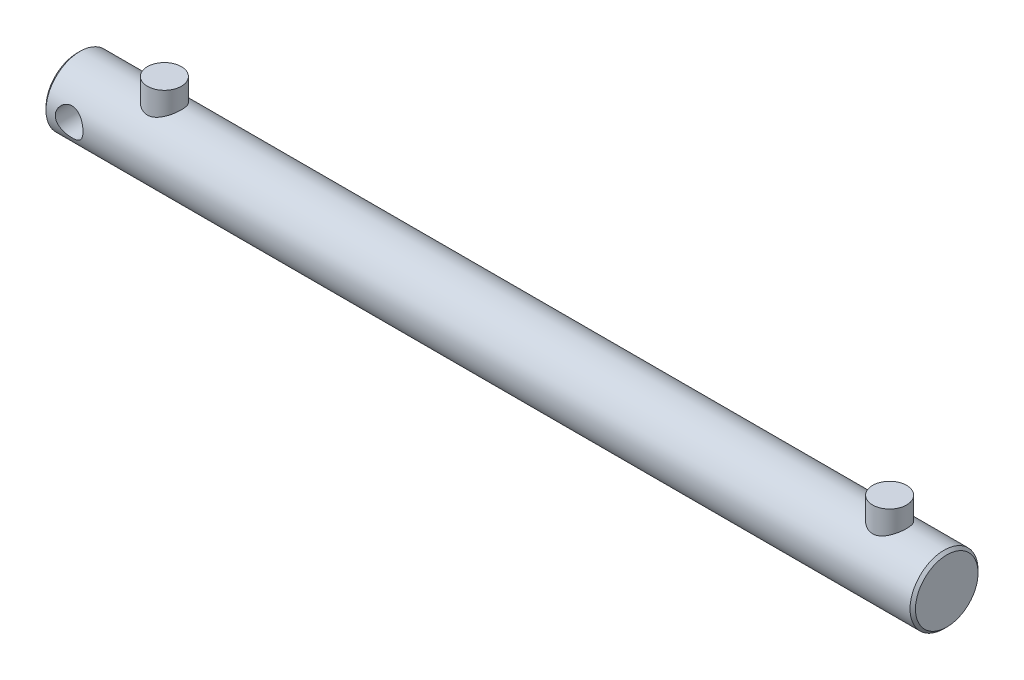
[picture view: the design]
ISO-10303-21;
HEADER;
FILE_DESCRIPTION(('STEP AP214'),'2;1');
FILE_NAME('part.step','',(''),(''),'','','');
FILE_SCHEMA(('AUTOMOTIVE_DESIGN { 1 0 10303 214 1 1 1 1 }'));
ENDSEC;
DATA;
#1=APPLICATION_CONTEXT('core data for automotive mechanical design processes');
#2=APPLICATION_PROTOCOL_DEFINITION('international standard','automotive_design',2000,#1);
#3=PRODUCT_CONTEXT('',#1,'mechanical');
#4=PRODUCT('Part','Part','',(#3));
#5=PRODUCT_RELATED_PRODUCT_CATEGORY('part','',(#4));
#6=PRODUCT_DEFINITION_FORMATION('','',#4);
#7=PRODUCT_DEFINITION_CONTEXT('part definition',#1,'design');
#8=PRODUCT_DEFINITION('design','',#6,#7);
#9=PRODUCT_DEFINITION_SHAPE('','',#8);
#10=(LENGTH_UNIT() NAMED_UNIT(*) SI_UNIT(.MILLI.,.METRE.));
#11=(NAMED_UNIT(*) PLANE_ANGLE_UNIT() SI_UNIT($,.RADIAN.));
#12=(NAMED_UNIT(*) SI_UNIT($,.STERADIAN.) SOLID_ANGLE_UNIT());
#13=UNCERTAINTY_MEASURE_WITH_UNIT(LENGTH_MEASURE(1.E-05),#10,'distance_accuracy_value','');
#14=(GEOMETRIC_REPRESENTATION_CONTEXT(3) GLOBAL_UNCERTAINTY_ASSIGNED_CONTEXT((#13)) GLOBAL_UNIT_ASSIGNED_CONTEXT((#10,
#11,#12)) REPRESENTATION_CONTEXT('',''));
#15=CARTESIAN_POINT('',(0.,0.,0.));
#16=DIRECTION('',(0.,0.,1.));
#17=DIRECTION('',(1.,0.,0.));
#18=AXIS2_PLACEMENT_3D('',#15,#16,#17);
#19=CARTESIAN_POINT('',(-319.5,0.,0.));
#20=DIRECTION('',(-1.,0.,0.));
#21=DIRECTION('',(0.,0.,1.));
#22=AXIS2_PLACEMENT_3D('',#19,#20,#21);
#23=CYLINDRICAL_SURFACE('',#22,25.);
#24=CARTESIAN_POINT('',(-255.5,21.6506350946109,-12.5));
#25=CARTESIAN_POINT('',(-255.825828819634,21.6506369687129,-12.4999985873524));
#26=CARTESIAN_POINT('',(-256.151686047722,21.6580155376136,-12.4872432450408));
#27=CARTESIAN_POINT('',(-256.800889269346,21.6872558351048,-12.4363891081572));
#28=CARTESIAN_POINT('',(-257.12423402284,21.7091243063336,-12.3982785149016));
#29=CARTESIAN_POINT('',(-257.766364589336,21.7665787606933,-12.297130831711));
#30=CARTESIAN_POINT('',(-258.085140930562,21.802189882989,-12.2340480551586));
#31=CARTESIAN_POINT('',(-258.715226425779,21.8858435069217,-12.0837589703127));
#32=CARTESIAN_POINT('',(-259.026536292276,21.9338848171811,-11.9965549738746));
#33=CARTESIAN_POINT('',(-259.638091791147,22.0405000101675,-11.7995262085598));
#34=CARTESIAN_POINT('',(-259.938389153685,22.0990140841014,-11.6898294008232));
#35=CARTESIAN_POINT('',(-260.528172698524,22.2249725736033,-11.4485414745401));
#36=CARTESIAN_POINT('',(-260.817654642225,22.2924204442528,-11.3169418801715));
#37=CARTESIAN_POINT('',(-261.667464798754,22.5052717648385,-10.8909843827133));
#38=CARTESIAN_POINT('',(-262.2097361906,22.6612898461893,-10.5652792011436));
#39=CARTESIAN_POINT('',(-263.278979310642,22.9996468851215,-9.80822889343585));
#40=CARTESIAN_POINT('',(-263.801000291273,23.1830954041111,-9.37038644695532));
#41=CARTESIAN_POINT('',(-264.525932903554,23.4556474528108,-8.65437620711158));
#42=CARTESIAN_POINT('',(-264.75804289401,23.5461267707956,-8.40562738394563));
#43=CARTESIAN_POINT('',(-265.201667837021,23.7240607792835,-7.88944454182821));
#44=CARTESIAN_POINT('',(-265.413190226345,23.8115165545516,-7.62201733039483));
#45=CARTESIAN_POINT('',(-265.827960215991,23.9870610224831,-7.0509634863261));
#46=CARTESIAN_POINT('',(-266.029675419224,24.0747909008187,-6.74611185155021));
#47=CARTESIAN_POINT('',(-266.406506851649,24.2419754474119,-6.11818329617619));
#48=CARTESIAN_POINT('',(-266.581621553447,24.3214296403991,-5.79510533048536));
#49=CARTESIAN_POINT('',(-266.90343651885,24.4697359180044,-5.13293948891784));
#50=CARTESIAN_POINT('',(-267.050150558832,24.5385931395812,-4.79385947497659));
#51=CARTESIAN_POINT('',(-267.313578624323,24.663681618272,-4.10199116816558));
#52=CARTESIAN_POINT('',(-267.430295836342,24.7199142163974,-3.74920433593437));
#53=CARTESIAN_POINT('',(-267.625035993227,24.8145076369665,-3.05827019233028));
#54=CARTESIAN_POINT('',(-267.70522088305,24.8538552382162,-2.72086672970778));
#55=CARTESIAN_POINT('',(-267.837413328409,24.9190379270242,-2.03929145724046));
#56=CARTESIAN_POINT('',(-267.889422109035,24.9448736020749,-1.69511994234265));
#57=CARTESIAN_POINT('',(-267.964549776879,24.9822725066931,-1.00304268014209));
#58=CARTESIAN_POINT('',(-267.987683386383,24.9938430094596,-0.655138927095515));
#59=CARTESIAN_POINT('',(-268.004785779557,25.0023919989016,0.04155519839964));
#60=CARTESIAN_POINT('',(-267.998756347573,24.9993713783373,0.390345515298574));
#61=CARTESIAN_POINT('',(-267.959420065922,24.9797298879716,1.05545670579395));
#62=CARTESIAN_POINT('',(-267.928534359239,24.9643162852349,1.3719600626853));
#63=CARTESIAN_POINT('',(-267.842896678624,24.9217919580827,2.00090286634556));
#64=CARTESIAN_POINT('',(-267.788146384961,24.8946820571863,2.31334259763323));
#65=CARTESIAN_POINT('',(-267.655375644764,24.8294144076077,2.93205832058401));
#66=CARTESIAN_POINT('',(-267.577354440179,24.7912562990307,3.2383341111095));
#67=CARTESIAN_POINT('',(-267.398835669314,24.7047808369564,3.8427892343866));
#68=CARTESIAN_POINT('',(-267.298337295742,24.6564631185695,4.14096827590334));
#69=CARTESIAN_POINT('',(-267.074267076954,24.5500266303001,4.73153890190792));
#70=CARTESIAN_POINT('',(-266.950396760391,24.4917821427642,5.02379438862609));
#71=CARTESIAN_POINT('',(-266.681577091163,24.367262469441,5.59664626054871));
#72=CARTESIAN_POINT('',(-266.536627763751,24.3009872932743,5.87724265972));
#73=CARTESIAN_POINT('',(-266.226722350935,24.1618170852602,6.42546402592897));
#74=CARTESIAN_POINT('',(-266.061764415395,24.0889214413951,6.69308779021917));
#75=CARTESIAN_POINT('',(-265.712866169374,23.9380009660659,7.21427443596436));
#76=CARTESIAN_POINT('',(-265.528918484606,23.8599741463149,7.46783179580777));
#77=CARTESIAN_POINT('',(-265.124909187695,23.6928666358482,7.98299107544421));
#78=CARTESIAN_POINT('',(-264.903077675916,23.6034377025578,8.24309375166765));
#79=CARTESIAN_POINT('',(-264.439270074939,23.4225308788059,8.74390948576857));
#80=CARTESIAN_POINT('',(-264.197292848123,23.331052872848,8.9846214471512));
#81=CARTESIAN_POINT('',(-263.694268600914,23.1482419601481,9.44565668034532));
#82=CARTESIAN_POINT('',(-263.433209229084,23.0569091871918,9.66596653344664));
#83=CARTESIAN_POINT('',(-262.893337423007,22.8767716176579,10.0849060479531));
#84=CARTESIAN_POINT('',(-262.614521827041,22.7879672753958,10.2835318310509));
#85=CARTESIAN_POINT('',(-262.022086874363,22.6097947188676,10.6698301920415));
#86=CARTESIAN_POINT('',(-261.707381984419,22.520752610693,10.8559934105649));
#87=CARTESIAN_POINT('',(-261.061183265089,22.3512779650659,11.2007713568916));
#88=CARTESIAN_POINT('',(-260.729697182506,22.2708415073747,11.3593986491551));
#89=CARTESIAN_POINT('',(-260.051996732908,22.1215174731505,11.6475234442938));
#90=CARTESIAN_POINT('',(-259.705791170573,22.0526231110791,11.7770380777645));
#91=CARTESIAN_POINT('',(-259.000945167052,21.9291206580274,12.0054389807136));
#92=CARTESIAN_POINT('',(-258.642306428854,21.874510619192,12.1043294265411));
#93=CARTESIAN_POINT('',(-257.944369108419,21.7856557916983,12.26347567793));
#94=CARTESIAN_POINT('',(-257.605788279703,21.7501406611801,12.3261709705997));
#95=CARTESIAN_POINT('',(-256.923342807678,21.6947067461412,12.4234802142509));
#96=CARTESIAN_POINT('',(-256.579478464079,21.6747870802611,12.4580957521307));
#97=CARTESIAN_POINT('',(-255.889711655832,21.6514003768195,12.4986965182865));
#98=CARTESIAN_POINT('',(-255.543810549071,21.6479233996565,12.5046990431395));
#99=CARTESIAN_POINT('',(-254.852946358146,21.657548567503,12.4880218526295));
#100=CARTESIAN_POINT('',(-254.50798321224,21.6706495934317,12.4653440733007));
#101=CARTESIAN_POINT('',(-253.859787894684,21.7105357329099,12.3957257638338));
#102=CARTESIAN_POINT('',(-253.556131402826,21.7356609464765,12.3517217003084));
#103=CARTESIAN_POINT('',(-252.953946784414,21.7977675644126,12.2417856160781));
#104=CARTESIAN_POINT('',(-252.655420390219,21.8347528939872,12.1758463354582));
#105=CARTESIAN_POINT('',(-252.065469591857,21.919415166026,12.0227647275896));
#106=CARTESIAN_POINT('',(-251.774044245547,21.9670906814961,11.9356252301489));
#107=CARTESIAN_POINT('',(-251.199706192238,22.0717635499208,11.7409310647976));
#108=CARTESIAN_POINT('',(-250.916796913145,22.1287645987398,11.6333683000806));
#109=CARTESIAN_POINT('',(-250.348184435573,22.2533312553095,11.3933466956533));
#110=CARTESIAN_POINT('',(-250.062947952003,22.3212614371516,11.2599724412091));
#111=CARTESIAN_POINT('',(-249.504535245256,22.4638079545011,10.9728312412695));
#112=CARTESIAN_POINT('',(-249.231364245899,22.5384271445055,10.8190555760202));
#113=CARTESIAN_POINT('',(-248.698252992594,22.692479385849,10.4920939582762));
#114=CARTESIAN_POINT('',(-248.438315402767,22.7719133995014,10.3189041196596));
#115=CARTESIAN_POINT('',(-247.932706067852,22.933742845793,9.95405785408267));
#116=CARTESIAN_POINT('',(-247.687035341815,23.0161384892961,9.76240011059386));
#117=CARTESIAN_POINT('',(-247.180799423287,23.192583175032,9.33615452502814));
#118=CARTESIAN_POINT('',(-246.922274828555,23.2867891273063,9.09920221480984));
#119=CARTESIAN_POINT('',(-246.425930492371,23.4741545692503,8.6043043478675));
#120=CARTESIAN_POINT('',(-246.188104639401,23.5673143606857,8.34636503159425));
#121=CARTESIAN_POINT('',(-245.734261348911,23.7502946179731,7.81048740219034));
#122=CARTESIAN_POINT('',(-245.518260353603,23.8401125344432,7.53253427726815));
#123=CARTESIAN_POINT('',(-245.109811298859,24.0139935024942,6.95830888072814));
#124=CARTESIAN_POINT('',(-244.917353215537,24.0980589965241,6.66204448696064));
#125=CARTESIAN_POINT('',(-244.552580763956,24.2604327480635,6.04450287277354));
#126=CARTESIAN_POINT('',(-244.380942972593,24.3385268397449,5.72276854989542));
#127=CARTESIAN_POINT('',(-244.065661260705,24.4841693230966,5.06353477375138));
#128=CARTESIAN_POINT('',(-243.922018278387,24.5517173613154,4.72603479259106));
#129=CARTESIAN_POINT('',(-243.664459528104,24.6742211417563,4.03792427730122));
#130=CARTESIAN_POINT('',(-243.55052252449,24.7291858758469,3.6873233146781));
#131=CARTESIAN_POINT('',(-243.353726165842,24.8248778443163,2.97561663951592));
#132=CARTESIAN_POINT('',(-243.270863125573,24.8656067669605,2.61451217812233));
#133=CARTESIAN_POINT('',(-243.143513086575,24.9284979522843,1.9185062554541));
#134=CARTESIAN_POINT('',(-243.096201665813,24.9520213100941,1.58424214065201));
#135=CARTESIAN_POINT('',(-243.028766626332,24.985611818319,0.912314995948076));
#136=CARTESIAN_POINT('',(-243.00864128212,24.9956798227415,0.574652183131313));
#137=CARTESIAN_POINT('',(-242.995841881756,25.0020787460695,-0.101219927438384));
#138=CARTESIAN_POINT('',(-243.003159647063,24.9984137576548,-0.439429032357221));
#139=CARTESIAN_POINT('',(-243.045132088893,24.9774578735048,-1.11371445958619));
#140=CARTESIAN_POINT('',(-243.079786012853,24.96016735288,-1.4497908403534));
#141=CARTESIAN_POINT('',(-243.172800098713,24.9140191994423,-2.09506424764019));
#142=CARTESIAN_POINT('',(-243.229444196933,24.8860005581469,-2.40457105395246));
#143=CARTESIAN_POINT('',(-243.365571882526,24.8191625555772,-3.01730683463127));
#144=CARTESIAN_POINT('',(-243.445054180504,24.7803438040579,-3.32053616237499));
#145=CARTESIAN_POINT('',(-243.626075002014,24.6927888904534,-3.91887965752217));
#146=CARTESIAN_POINT('',(-243.727615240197,24.644051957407,-4.21399319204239));
#147=CARTESIAN_POINT('',(-243.951830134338,24.5377360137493,-4.79443241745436));
#148=CARTESIAN_POINT('',(-244.074505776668,24.4801565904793,-5.07975765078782));
#149=CARTESIAN_POINT('',(-244.345646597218,24.3547642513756,-5.65106966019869));
#150=CARTESIAN_POINT('',(-244.494986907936,24.2866201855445,-5.93656816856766));
#151=CARTESIAN_POINT('',(-244.814454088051,24.1435393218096,-6.49402514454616));
#152=CARTESIAN_POINT('',(-244.984588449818,24.0686000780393,-6.76597868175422));
#153=CARTESIAN_POINT('',(-245.344503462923,23.9135470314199,-7.29508667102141));
#154=CARTESIAN_POINT('',(-245.534288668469,23.8334320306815,-7.55223767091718));
#155=CARTESIAN_POINT('',(-245.93236125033,23.6697443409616,-8.05059010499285));
#156=CARTESIAN_POINT('',(-246.140648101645,23.5861717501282,-8.29179199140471));
#157=CARTESIAN_POINT('',(-246.596332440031,23.4089075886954,-8.78049915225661));
#158=CARTESIAN_POINT('',(-246.845558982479,23.3150375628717,-9.02623729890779));
#159=CARTESIAN_POINT('',(-247.363805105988,23.1276739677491,-9.49603431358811));
#160=CARTESIAN_POINT('',(-247.632825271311,23.0341804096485,-9.72009254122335));
#161=CARTESIAN_POINT('',(-248.189584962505,22.8500132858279,-10.1454748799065));
#162=CARTESIAN_POINT('',(-248.477340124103,22.7593421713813,-10.3467796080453));
#163=CARTESIAN_POINT('',(-249.07002865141,22.5834994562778,-10.7251617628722));
#164=CARTESIAN_POINT('',(-249.374964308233,22.498328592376,-10.9022359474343));
#165=CARTESIAN_POINT('',(-250.010467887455,22.3335584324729,-11.2360101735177));
#166=CARTESIAN_POINT('',(-250.341543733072,22.2542245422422,-11.3918772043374));
#167=CARTESIAN_POINT('',(-251.018159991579,22.1071923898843,-11.6746502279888));
#168=CARTESIAN_POINT('',(-251.363692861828,22.0394881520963,-11.8015711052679));
#169=CARTESIAN_POINT('',(-252.066013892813,21.9185525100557,-12.0246888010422));
#170=CARTESIAN_POINT('',(-252.422770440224,21.8652839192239,-12.1209646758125));
#171=CARTESIAN_POINT('',(-253.145231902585,21.7753691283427,-12.2817688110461));
#172=CARTESIAN_POINT('',(-253.510930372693,21.7387113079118,-12.346319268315));
#173=CARTESIAN_POINT('',(-254.147494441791,21.6911886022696,-12.4295575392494));
#174=CARTESIAN_POINT('',(-254.417060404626,21.6760179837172,-12.4559482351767));
#175=CARTESIAN_POINT('',(-254.957744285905,21.6557401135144,-12.4911706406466));
#176=CARTESIAN_POINT('',(-255.228862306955,21.6506335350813,-12.5000011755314));
#177=CARTESIAN_POINT('',(-255.5,21.6506350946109,-12.5));
#178=B_SPLINE_CURVE_WITH_KNOTS('',3,(#24,#25,#26,#27,#28,#29,#30,#31,#32,#33,#34,#35,#36,#37,
#38,#39,#40,#41,#42,#43,#44,#45,#46,#47,#48,#49,#50,#51,#52,#53,#54,#55,#56,#57,#58,#59,#60,#61,
#62,#63,#64,#65,#66,#67,#68,#69,#70,#71,#72,#73,#74,#75,#76,#77,#78,#79,#80,#81,#82,#83,#84,#85,
#86,#87,#88,#89,#90,#91,#92,#93,#94,#95,#96,#97,#98,#99,#100,#101,#102,#103,#104,#105,#106,#107,
#108,#109,#110,#111,#112,#113,#114,#115,#116,#117,#118,#119,#120,#121,#122,#123,#124,#125,#126,
#127,#128,#129,#130,#131,#132,#133,#134,#135,#136,#137,#138,#139,#140,#141,#142,#143,#144,#145,
#146,#147,#148,#149,#150,#151,#152,#153,#154,#155,#156,#157,#158,#159,#160,#161,#162,#163,#164,
#165,#166,#167,#168,#169,#170,#171,#172,#173,#174,#175,#176,#177),.UNSPECIFIED.,.T.,.F.,(4,2,2,
2,2,2,2,2,2,2,2,2,2,2,2,2,2,2,2,2,2,2,2,2,2,2,2,2,2,2,2,2,2,2,2,2,2,2,2,2,2,2,2,2,2,2,2,2,2,2,2,
2,2,2,2,2,2,2,2,2,2,2,2,2,2,2,2,2,2,2,2,2,2,2,2,2,4),(0.,0.977205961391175,1.95486696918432,
2.93432493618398,3.91368906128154,4.88762893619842,5.86194658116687,7.80874820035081,
9.91611803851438,10.9713526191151,12.0262045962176,13.1525478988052,14.2789558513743,
15.4048160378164,16.5305565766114,17.5762155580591,18.6218290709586,19.6669092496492,
20.7119254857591,21.6659378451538,22.6198830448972,23.5738593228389,24.5278698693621,
25.4950080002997,26.4621449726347,27.4293714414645,28.39697493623,29.4558985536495,
30.514882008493,31.5745570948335,32.6344214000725,33.7619649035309,34.8889925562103,
36.015355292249,37.1415643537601,38.17858119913,39.2155394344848,40.251870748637,
41.2881321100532,42.2106469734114,43.1334674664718,44.0561648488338,44.9792288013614,
45.9446183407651,46.9104218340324,47.8764189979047,48.8424850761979,49.9306247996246,
51.0184421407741,52.1070729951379,53.1952387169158,54.3125134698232,55.429825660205,
56.5463369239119,57.6627157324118,58.6766202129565,59.6904603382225,60.7039983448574,
61.7175084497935,62.6641089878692,63.6106560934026,64.5572768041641,65.5039417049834,
66.4908805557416,67.478176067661,68.4657009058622,69.4531977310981,70.5391008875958,
71.6250361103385,72.71188954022,73.7988882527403,74.9206611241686,76.0418558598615,
77.1601343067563,78.2776292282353,79.0907545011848,79.9039341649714),.UNSPECIFIED.);
#179=CARTESIAN_POINT('',(-255.5,21.6506350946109,-12.5));
#180=VERTEX_POINT('',#179);
#181=EDGE_CURVE('E38',#180,#180,#178,.T.);
#182=ORIENTED_EDGE('',*,*,#181,.F.);
#183=EDGE_LOOP('',(#182));
#184=FACE_BOUND('',#183,.T.);
#185=CARTESIAN_POINT('',(-290.3,0.,-24.9999999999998));
#186=CARTESIAN_POINT('',(-290.300001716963,0.27378943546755,-24.9999986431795));
#187=CARTESIAN_POINT('',(-290.311038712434,0.547678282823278,-24.9954899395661));
#188=CARTESIAN_POINT('',(-290.355085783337,1.09351246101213,-24.9775677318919));
#189=CARTESIAN_POINT('',(-290.388110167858,1.36545640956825,-24.9641484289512));
#190=CARTESIAN_POINT('',(-290.475895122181,1.90589153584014,-24.9287196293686));
#191=CARTESIAN_POINT('',(-290.530705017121,2.17437344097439,-24.9066906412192));
#192=CARTESIAN_POINT('',(-290.661508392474,2.70533868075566,-24.8546237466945));
#193=CARTESIAN_POINT('',(-290.737503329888,2.96782160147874,-24.8245852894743));
#194=CARTESIAN_POINT('',(-290.909657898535,3.48412634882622,-24.7573909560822));
#195=CARTESIAN_POINT('',(-291.005747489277,3.73797478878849,-24.7202598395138));
#196=CARTESIAN_POINT('',(-291.217413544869,4.23637900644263,-24.6397409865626));
#197=CARTESIAN_POINT('',(-291.332990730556,4.48093443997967,-24.5963530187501));
#198=CARTESIAN_POINT('',(-291.582658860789,4.95920699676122,-24.5043977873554));
#199=CARTESIAN_POINT('',(-291.71673892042,5.19293038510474,-24.4558335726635));
#200=CARTESIAN_POINT('',(-292.002515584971,5.64846413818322,-24.3546587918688));
#201=CARTESIAN_POINT('',(-292.154218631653,5.87027010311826,-24.3020467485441));
#202=CARTESIAN_POINT('',(-292.648401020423,6.53495483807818,-24.1352121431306));
#203=CARTESIAN_POINT('',(-293.019052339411,6.95614665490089,-24.016166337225));
#204=CARTESIAN_POINT('',(-293.824387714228,7.73234580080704,-23.7776427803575));
#205=CARTESIAN_POINT('',(-294.259104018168,8.08731959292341,-23.6581648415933));
#206=CARTESIAN_POINT('',(-294.962487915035,8.57101087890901,-23.4855059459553));
#207=CARTESIAN_POINT('',(-295.211689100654,8.72699363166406,-23.4278402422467));
#208=CARTESIAN_POINT('',(-295.723454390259,9.01726356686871,-23.3176551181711));
#209=CARTESIAN_POINT('',(-295.986012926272,9.1515596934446,-23.2651335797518));
#210=CARTESIAN_POINT('',(-296.522800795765,9.39728813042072,-23.1669700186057));
#211=CARTESIAN_POINT('',(-296.797028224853,9.50872415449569,-23.1213268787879));
#212=CARTESIAN_POINT('',(-297.355281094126,9.70765251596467,-23.0385135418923));
#213=CARTESIAN_POINT('',(-297.63930583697,9.79514655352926,-23.0013427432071));
#214=CARTESIAN_POINT('',(-298.20152230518,9.9417006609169,-22.9383663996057));
#215=CARTESIAN_POINT('',(-298.479367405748,10.0018973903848,-22.9121113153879));
#216=CARTESIAN_POINT('',(-299.039859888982,10.0989538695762,-22.8694982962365));
#217=CARTESIAN_POINT('',(-299.322507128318,10.1358143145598,-22.8531400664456));
#218=CARTESIAN_POINT('',(-299.890181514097,10.1857387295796,-22.830932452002));
#219=CARTESIAN_POINT('',(-300.17520754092,10.1988133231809,-22.8250783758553));
#220=CARTESIAN_POINT('',(-300.745364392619,10.2010320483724,-22.8240871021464));
#221=CARTESIAN_POINT('',(-301.030495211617,10.1901773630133,-22.8289493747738));
#222=CARTESIAN_POINT('',(-301.577650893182,10.1463488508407,-22.8484597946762));
#223=CARTESIAN_POINT('',(-301.839838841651,10.1150529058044,-22.862365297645));
#224=CARTESIAN_POINT('',(-302.360508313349,10.0323483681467,-22.8987778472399));
#225=CARTESIAN_POINT('',(-302.618988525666,9.98093283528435,-22.9212878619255));
#226=CARTESIAN_POINT('',(-303.130362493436,9.85851435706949,-22.9742057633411));
#227=CARTESIAN_POINT('',(-303.383257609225,9.78751623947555,-23.004611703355));
#228=CARTESIAN_POINT('',(-303.882066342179,9.62654350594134,-23.0724355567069));
#229=CARTESIAN_POINT('',(-304.127977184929,9.53656146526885,-23.1098562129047));
#230=CARTESIAN_POINT('',(-304.616250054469,9.3363549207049,-23.1914724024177));
#231=CARTESIAN_POINT('',(-304.858437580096,9.22575520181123,-23.2357904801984));
#232=CARTESIAN_POINT('',(-305.332771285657,8.98637481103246,-23.3294145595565));
#233=CARTESIAN_POINT('',(-305.564913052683,8.85758625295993,-23.3787227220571));
#234=CARTESIAN_POINT('',(-306.017893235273,8.58271796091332,-23.4810232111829));
#235=CARTESIAN_POINT('',(-306.238730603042,8.43663662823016,-23.5340158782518));
#236=CARTESIAN_POINT('',(-306.668018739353,8.12806439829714,-23.6423625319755));
#237=CARTESIAN_POINT('',(-306.876468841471,7.9655726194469,-23.6977166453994));
#238=CARTESIAN_POINT('',(-307.296327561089,7.61126566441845,-23.8139905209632));
#239=CARTESIAN_POINT('',(-307.506609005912,7.41814148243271,-23.8749980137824));
#240=CARTESIAN_POINT('',(-307.910247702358,7.01495391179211,-23.996556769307));
#241=CARTESIAN_POINT('',(-308.103610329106,6.80489594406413,-24.0571081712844));
#242=CARTESIAN_POINT('',(-308.472422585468,6.36883544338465,-24.1762081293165));
#243=CARTESIAN_POINT('',(-308.647861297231,6.1428233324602,-24.2347554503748));
#244=CARTESIAN_POINT('',(-308.979444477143,5.67634341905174,-24.3482384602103));
#245=CARTESIAN_POINT('',(-309.135596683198,5.43588147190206,-24.4031755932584));
#246=CARTESIAN_POINT('',(-309.430678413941,4.93648649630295,-24.5091338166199));
#247=CARTESIAN_POINT('',(-309.569162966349,4.67726664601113,-24.5600446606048));
#248=CARTESIAN_POINT('',(-309.823651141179,4.14681343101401,-24.6551522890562));
#249=CARTESIAN_POINT('',(-309.939654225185,3.87557977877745,-24.6993489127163));
#250=CARTESIAN_POINT('',(-310.147996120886,3.32314262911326,-24.7797213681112));
#251=CARTESIAN_POINT('',(-310.240345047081,3.04194345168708,-24.8159006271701));
#252=CARTESIAN_POINT('',(-310.400441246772,2.47163195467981,-24.8791744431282));
#253=CARTESIAN_POINT('',(-310.468190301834,2.18252020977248,-24.9062696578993));
#254=CARTESIAN_POINT('',(-310.574934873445,1.616619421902,-24.9491899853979));
#255=CARTESIAN_POINT('',(-310.615435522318,1.3401581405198,-24.9656030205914));
#256=CARTESIAN_POINT('',(-310.673625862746,0.784456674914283,-24.9892367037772));
#257=CARTESIAN_POINT('',(-310.691316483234,0.505216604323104,-24.9964577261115));
#258=CARTESIAN_POINT('',(-310.703688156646,-0.053790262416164,-25.0015043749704));
#259=CARTESIAN_POINT('',(-310.698374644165,-0.333556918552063,-24.9993322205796));
#260=CARTESIAN_POINT('',(-310.66481007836,-0.89147694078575,-24.9856584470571));
#261=CARTESIAN_POINT('',(-310.636559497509,-1.16963033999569,-24.9741570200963));
#262=CARTESIAN_POINT('',(-310.559307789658,-1.70910499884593,-24.9429047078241));
#263=CARTESIAN_POINT('',(-310.511349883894,-1.97060070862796,-24.9235691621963));
#264=CARTESIAN_POINT('',(-310.395366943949,-2.48839302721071,-24.8772076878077));
#265=CARTESIAN_POINT('',(-310.327342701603,-2.74468984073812,-24.8501820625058));
#266=CARTESIAN_POINT('',(-310.171853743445,-3.25041966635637,-24.7891034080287));
#267=CARTESIAN_POINT('',(-310.084390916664,-3.4998533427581,-24.7550510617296));
#268=CARTESIAN_POINT('',(-309.890723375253,-3.99047626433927,-24.6807149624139));
#269=CARTESIAN_POINT('',(-309.784511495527,-4.23166231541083,-24.640428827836));
#270=CARTESIAN_POINT('',(-309.550676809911,-4.7115437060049,-24.5532610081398));
#271=CARTESIAN_POINT('',(-309.422500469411,-4.94993951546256,-24.5062158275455));
#272=CARTESIAN_POINT('',(-309.148039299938,-5.41520072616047,-24.4076254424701));
#273=CARTESIAN_POINT('',(-309.001747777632,-5.64206182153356,-24.3560785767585));
#274=CARTESIAN_POINT('',(-308.692041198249,-6.08301428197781,-24.2497090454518));
#275=CARTESIAN_POINT('',(-308.528623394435,-6.29710359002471,-24.1948858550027));
#276=CARTESIAN_POINT('',(-308.185662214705,-6.71140238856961,-24.083253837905));
#277=CARTESIAN_POINT('',(-308.0061180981,-6.91161124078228,-24.026444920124));
#278=CARTESIAN_POINT('',(-307.618984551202,-7.31043905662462,-23.9082343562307));
#279=CARTESIAN_POINT('',(-307.410315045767,-7.50799727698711,-23.8467860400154));
#280=CARTESIAN_POINT('',(-306.97699477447,-7.88485612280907,-23.7248448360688));
#281=CARTESIAN_POINT('',(-306.752350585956,-8.0641641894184,-23.6643515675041));
#282=CARTESIAN_POINT('',(-306.288119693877,-8.4035944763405,-23.5459537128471));
#283=CARTESIAN_POINT('',(-306.048523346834,-8.56370411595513,-23.4880508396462));
#284=CARTESIAN_POINT('',(-305.555996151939,-8.86340597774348,-23.3766035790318));
#285=CARTESIAN_POINT('',(-305.303071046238,-9.00300693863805,-23.3230573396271));
#286=CARTESIAN_POINT('',(-304.782108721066,-9.26224753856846,-23.22133525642));
#287=CARTESIAN_POINT('',(-304.51392354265,-9.3816196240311,-23.1732338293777));
#288=CARTESIAN_POINT('',(-303.967252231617,-9.59710554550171,-23.0848248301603));
#289=CARTESIAN_POINT('',(-303.688770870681,-9.69323000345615,-23.0445137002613));
#290=CARTESIAN_POINT('',(-303.12354634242,-9.86123160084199,-22.9731245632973));
#291=CARTESIAN_POINT('',(-302.836806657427,-9.93311880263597,-22.9420427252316));
#292=CARTESIAN_POINT('',(-302.25726859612,-10.0518392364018,-22.890276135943));
#293=CARTESIAN_POINT('',(-301.964470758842,-10.0986746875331,-22.8695904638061));
#294=CARTESIAN_POINT('',(-301.397283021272,-10.1641633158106,-22.8405550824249));
#295=CARTESIAN_POINT('',(-301.123145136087,-10.1846546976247,-22.8314017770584));
#296=CARTESIAN_POINT('',(-300.573963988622,-10.2034310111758,-22.8230170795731));
#297=CARTESIAN_POINT('',(-300.298920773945,-10.2017170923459,-22.8237851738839));
#298=CARTESIAN_POINT('',(-299.750116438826,-10.176105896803,-22.8352153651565));
#299=CARTESIAN_POINT('',(-299.476355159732,-10.1522114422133,-22.8458762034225));
#300=CARTESIAN_POINT('',(-298.932183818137,-10.0825193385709,-22.8767185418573));
#301=CARTESIAN_POINT('',(-298.661773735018,-10.0367218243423,-22.8968999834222));
#302=CARTESIAN_POINT('',(-298.137843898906,-9.92616689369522,-22.9450358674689));
#303=CARTESIAN_POINT('',(-297.884098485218,-9.86231170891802,-22.9726178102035));
#304=CARTESIAN_POINT('',(-297.382997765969,-9.715579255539,-23.03505747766));
#305=CARTESIAN_POINT('',(-297.135644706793,-9.63269539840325,-23.0699177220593));
#306=CARTESIAN_POINT('',(-296.648856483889,-9.44861946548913,-23.1459174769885));
#307=CARTESIAN_POINT('',(-296.409421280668,-9.34742748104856,-23.1870569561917));
#308=CARTESIAN_POINT('',(-295.939722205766,-9.12749285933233,-23.2745112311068));
#309=CARTESIAN_POINT('',(-295.709459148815,-9.0087486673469,-23.320826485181));
#310=CARTESIAN_POINT('',(-295.246047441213,-8.74704987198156,-23.4202869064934));
#311=CARTESIAN_POINT('',(-295.013521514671,-8.60308382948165,-23.4736733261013));
#312=CARTESIAN_POINT('',(-294.561253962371,-8.29733760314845,-23.5834808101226));
#313=CARTESIAN_POINT('',(-294.341512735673,-8.13555686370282,-23.6399019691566));
#314=CARTESIAN_POINT('',(-293.91587364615,-7.79509906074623,-23.7543403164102));
#315=CARTESIAN_POINT('',(-293.709979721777,-7.61641722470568,-23.8123579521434));
#316=CARTESIAN_POINT('',(-293.313168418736,-7.24317940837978,-23.9285300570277));
#317=CARTESIAN_POINT('',(-293.122251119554,-7.04862334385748,-23.9866845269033));
#318=CARTESIAN_POINT('',(-292.743809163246,-6.63071217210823,-24.1056847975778));
#319=CARTESIAN_POINT('',(-292.55742501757,-6.40629638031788,-24.1664398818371));
#320=CARTESIAN_POINT('',(-292.204265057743,-5.94187315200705,-24.2848006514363));
#321=CARTESIAN_POINT('',(-292.037482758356,-5.70187091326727,-24.342407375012));
#322=CARTESIAN_POINT('',(-291.724582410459,-5.20746466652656,-24.4529448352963));
#323=CARTESIAN_POINT('',(-291.578479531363,-4.95305027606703,-24.5058721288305));
#324=CARTESIAN_POINT('',(-291.308321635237,-4.43161956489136,-24.605511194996));
#325=CARTESIAN_POINT('',(-291.184264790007,-4.16460429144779,-24.652223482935));
#326=CARTESIAN_POINT('',(-290.961330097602,-3.62458274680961,-24.7373360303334));
#327=CARTESIAN_POINT('',(-290.862047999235,-3.35176427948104,-24.7758679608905));
#328=CARTESIAN_POINT('',(-290.686882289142,-2.79769806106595,-24.8445322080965));
#329=CARTESIAN_POINT('',(-290.610996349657,-2.51645115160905,-24.8746653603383));
#330=CARTESIAN_POINT('',(-290.483615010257,-1.94846806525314,-24.925580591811));
#331=CARTESIAN_POINT('',(-290.432054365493,-1.66174874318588,-24.9463876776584));
#332=CARTESIAN_POINT('',(-290.353648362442,-1.08455530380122,-24.9781334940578));
#333=CARTESIAN_POINT('',(-290.326784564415,-0.794084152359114,-24.9890795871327));
#334=CARTESIAN_POINT('',(-290.308274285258,-0.419253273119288,-24.9966251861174));
#335=CARTESIAN_POINT('',(-290.305172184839,-0.335440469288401,-24.9978901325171));
#336=CARTESIAN_POINT('',(-290.301034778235,-0.167754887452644,-24.9995777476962));
#337=CARTESIAN_POINT('',(-290.299999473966,-0.0838821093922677,-25.000000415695));
#338=CARTESIAN_POINT('',(-290.3,0.,-24.9999999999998));
#339=B_SPLINE_CURVE_WITH_KNOTS('',3,(#185,#186,#187,#188,#189,#190,#191,#192,#193,#194,#195,
#196,#197,#198,#199,#200,#201,#202,#203,#204,#205,#206,#207,#208,#209,#210,#211,#212,#213,#214,
#215,#216,#217,#218,#219,#220,#221,#222,#223,#224,#225,#226,#227,#228,#229,#230,#231,#232,#233,
#234,#235,#236,#237,#238,#239,#240,#241,#242,#243,#244,#245,#246,#247,#248,#249,#250,#251,#252,
#253,#254,#255,#256,#257,#258,#259,#260,#261,#262,#263,#264,#265,#266,#267,#268,#269,#270,#271,
#272,#273,#274,#275,#276,#277,#278,#279,#280,#281,#282,#283,#284,#285,#286,#287,#288,#289,#290,
#291,#292,#293,#294,#295,#296,#297,#298,#299,#300,#301,#302,#303,#304,#305,#306,#307,#308,#309,
#310,#311,#312,#313,#314,#315,#316,#317,#318,#319,#320,#321,#322,#323,#324,#325,#326,#327,#328,
#329,#330,#331,#332,#333,#334,#335,#336,#337,#338),.UNSPECIFIED.,.T.,.F.,(4,2,2,2,2,2,2,2,2,2,2,
2,2,2,2,2,2,2,2,2,2,2,2,2,2,2,2,2,2,2,2,2,2,2,2,2,2,2,2,2,2,2,2,2,2,2,2,2,2,2,2,2,2,2,2,2,2,2,2,
2,2,2,2,2,2,2,2,2,2,2,2,2,2,2,2,2,4),(0.,0.821282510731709,1.6431000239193,2.46678893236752,
3.29053450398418,4.11145536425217,4.93240659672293,5.752876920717,6.5736481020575,
8.28632730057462,9.9998715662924,10.8977043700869,11.7951659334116,12.6924815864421,
13.5897335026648,14.4451011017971,15.3004432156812,16.1554032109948,17.0103209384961,
17.8026371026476,18.5952268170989,19.3876213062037,20.1803262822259,20.9891888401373,
21.7984031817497,22.6076923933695,23.4170251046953,24.2918919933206,25.166479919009,
26.0415974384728,26.9163627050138,27.8100268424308,28.7037123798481,29.5970151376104,
30.4902531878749,31.3288614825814,32.1674356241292,33.0058116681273,33.844170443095,
34.6429279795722,35.4416540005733,36.2403024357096,37.039256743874,37.8625419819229,
38.6861323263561,39.5098549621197,40.3336154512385,41.2141546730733,42.0943334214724,
42.9750858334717,43.8554618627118,44.7467007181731,45.6375315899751,46.5279921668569,
47.4183738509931,48.2424819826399,49.066547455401,49.8905080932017,50.71446365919,
51.5029072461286,52.2916242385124,53.0803372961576,53.8691202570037,54.7041620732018,
55.5392299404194,56.374534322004,57.2098431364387,58.1027169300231,58.9952944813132,
59.8885234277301,60.7816782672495,61.6591338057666,62.5365020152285,63.4115033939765,
64.2858509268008,64.5374707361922,64.7890907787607),.UNSPECIFIED.);
#340=CARTESIAN_POINT('',(-290.3,0.,-24.9999999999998));
#341=VERTEX_POINT('',#340);
#342=EDGE_CURVE('E42',#341,#341,#339,.T.);
#343=ORIENTED_EDGE('',*,*,#342,.T.);
#344=EDGE_LOOP('',(#343));
#345=FACE_BOUND('',#344,.T.);
#346=CARTESIAN_POINT('',(-290.3,0.,25.0000000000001));
#347=CARTESIAN_POINT('',(-290.300001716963,-0.273789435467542,24.9999986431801));
#348=CARTESIAN_POINT('',(-290.311038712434,-0.547678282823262,24.9954899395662));
#349=CARTESIAN_POINT('',(-290.355085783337,-1.09351246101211,24.9775677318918));
#350=CARTESIAN_POINT('',(-290.388110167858,-1.36545640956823,24.9641484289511));
#351=CARTESIAN_POINT('',(-290.475895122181,-1.90589153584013,24.9287196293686));
#352=CARTESIAN_POINT('',(-290.530705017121,-2.17437344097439,24.9066906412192));
#353=CARTESIAN_POINT('',(-290.661508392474,-2.70533868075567,24.8546237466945));
#354=CARTESIAN_POINT('',(-290.737503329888,-2.96782160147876,24.8245852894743));
#355=CARTESIAN_POINT('',(-290.909657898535,-3.48412634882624,24.7573909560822));
#356=CARTESIAN_POINT('',(-291.005747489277,-3.73797478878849,24.7202598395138));
#357=CARTESIAN_POINT('',(-291.217413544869,-4.23637900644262,24.6397409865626));
#358=CARTESIAN_POINT('',(-291.332990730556,-4.48093443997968,24.5963530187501));
#359=CARTESIAN_POINT('',(-291.582658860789,-4.95920699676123,24.5043977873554));
#360=CARTESIAN_POINT('',(-291.71673892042,-5.19293038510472,24.4558335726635));
#361=CARTESIAN_POINT('',(-292.002515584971,-5.6484641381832,24.3546587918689));
#362=CARTESIAN_POINT('',(-292.154218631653,-5.87027010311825,24.3020467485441));
#363=CARTESIAN_POINT('',(-292.648401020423,-6.53495483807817,24.1352121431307));
#364=CARTESIAN_POINT('',(-293.019052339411,-6.95614665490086,24.016166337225));
#365=CARTESIAN_POINT('',(-293.824387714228,-7.73234580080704,23.7776427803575));
#366=CARTESIAN_POINT('',(-294.259104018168,-8.08731959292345,23.6581648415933));
#367=CARTESIAN_POINT('',(-294.962487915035,-8.57101087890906,23.4855059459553));
#368=CARTESIAN_POINT('',(-295.211689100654,-8.72699363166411,23.4278402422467));
#369=CARTESIAN_POINT('',(-295.723454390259,-9.01726356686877,23.3176551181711));
#370=CARTESIAN_POINT('',(-295.986012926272,-9.15155969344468,23.2651335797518));
#371=CARTESIAN_POINT('',(-296.522800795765,-9.39728813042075,23.1669700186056));
#372=CARTESIAN_POINT('',(-296.797028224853,-9.50872415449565,23.1213268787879));
#373=CARTESIAN_POINT('',(-297.355281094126,-9.70765251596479,23.0385135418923));
#374=CARTESIAN_POINT('',(-297.63930583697,-9.7951465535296,23.0013427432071));
#375=CARTESIAN_POINT('',(-298.20152230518,-9.94170066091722,22.9383663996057));
#376=CARTESIAN_POINT('',(-298.479367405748,-10.0018973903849,22.9121113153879));
#377=CARTESIAN_POINT('',(-299.039859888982,-10.0989538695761,22.8694982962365));
#378=CARTESIAN_POINT('',(-299.322507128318,-10.1358143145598,22.8531400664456));
#379=CARTESIAN_POINT('',(-299.890181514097,-10.1857387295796,22.830932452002));
#380=CARTESIAN_POINT('',(-300.17520754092,-10.1988133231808,22.8250783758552));
#381=CARTESIAN_POINT('',(-300.745364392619,-10.2010320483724,22.8240871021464));
#382=CARTESIAN_POINT('',(-301.030495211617,-10.1901773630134,22.828949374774));
#383=CARTESIAN_POINT('',(-301.577650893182,-10.1463488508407,22.8484597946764));
#384=CARTESIAN_POINT('',(-301.839838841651,-10.1150529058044,22.8623652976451));
#385=CARTESIAN_POINT('',(-302.360508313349,-10.0323483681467,22.8987778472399));
#386=CARTESIAN_POINT('',(-302.618988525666,-9.98093283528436,22.9212878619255));
#387=CARTESIAN_POINT('',(-303.130362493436,-9.85851435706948,22.9742057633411));
#388=CARTESIAN_POINT('',(-303.383257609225,-9.7875162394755,23.004611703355));
#389=CARTESIAN_POINT('',(-303.882066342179,-9.62654350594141,23.0724355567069));
#390=CARTESIAN_POINT('',(-304.127977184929,-9.53656146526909,23.1098562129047));
#391=CARTESIAN_POINT('',(-304.616250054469,-9.33635492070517,23.1914724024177));
#392=CARTESIAN_POINT('',(-304.858437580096,-9.22575520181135,23.2357904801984));
#393=CARTESIAN_POINT('',(-305.332771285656,-8.98637481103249,23.3294145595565));
#394=CARTESIAN_POINT('',(-305.564913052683,-8.85758625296,23.3787227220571));
#395=CARTESIAN_POINT('',(-306.017893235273,-8.58271796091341,23.4810232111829));
#396=CARTESIAN_POINT('',(-306.238730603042,-8.4366366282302,23.5340158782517));
#397=CARTESIAN_POINT('',(-306.668018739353,-8.12806439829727,23.6423625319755));
#398=CARTESIAN_POINT('',(-306.876468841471,-7.96557261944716,23.6977166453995));
#399=CARTESIAN_POINT('',(-307.296327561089,-7.61126566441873,23.8139905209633));
#400=CARTESIAN_POINT('',(-307.506609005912,-7.41814148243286,23.8749980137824));
#401=CARTESIAN_POINT('',(-307.910247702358,-7.01495391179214,23.9965567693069));
#402=CARTESIAN_POINT('',(-308.103610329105,-6.80489594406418,24.0571081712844));
#403=CARTESIAN_POINT('',(-308.472422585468,-6.36883544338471,24.1762081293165));
#404=CARTESIAN_POINT('',(-308.647861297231,-6.14282333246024,24.2347554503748));
#405=CARTESIAN_POINT('',(-308.979444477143,-5.67634341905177,24.3482384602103));
#406=CARTESIAN_POINT('',(-309.135596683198,-5.43588147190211,24.4031755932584));
#407=CARTESIAN_POINT('',(-309.430678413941,-4.93648649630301,24.5091338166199));
#408=CARTESIAN_POINT('',(-309.569162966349,-4.67726664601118,24.5600446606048));
#409=CARTESIAN_POINT('',(-309.823651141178,-4.14681343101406,24.6551522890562));
#410=CARTESIAN_POINT('',(-309.939654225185,-3.87557977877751,24.6993489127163));
#411=CARTESIAN_POINT('',(-310.147996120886,-3.32314262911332,24.7797213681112));
#412=CARTESIAN_POINT('',(-310.240345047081,-3.04194345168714,24.8159006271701));
#413=CARTESIAN_POINT('',(-310.400441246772,-2.47163195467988,24.8791744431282));
#414=CARTESIAN_POINT('',(-310.468190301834,-2.18252020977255,24.9062696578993));
#415=CARTESIAN_POINT('',(-310.574934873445,-1.61661942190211,24.9491899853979));
#416=CARTESIAN_POINT('',(-310.615435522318,-1.34015814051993,24.9656030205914));
#417=CARTESIAN_POINT('',(-310.673625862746,-0.784456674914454,24.9892367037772));
#418=CARTESIAN_POINT('',(-310.691316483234,-0.505216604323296,24.9964577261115));
#419=CARTESIAN_POINT('',(-310.703688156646,0.0537902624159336,25.0015043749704));
#420=CARTESIAN_POINT('',(-310.698374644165,0.333556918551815,24.9993322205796));
#421=CARTESIAN_POINT('',(-310.66481007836,0.89147694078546,24.9856584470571));
#422=CARTESIAN_POINT('',(-310.636559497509,1.16963033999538,24.9741570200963));
#423=CARTESIAN_POINT('',(-310.559307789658,1.70910499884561,24.9429047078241));
#424=CARTESIAN_POINT('',(-310.511349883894,1.97060070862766,24.9235691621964));
#425=CARTESIAN_POINT('',(-310.395366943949,2.48839302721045,24.8772076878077));
#426=CARTESIAN_POINT('',(-310.327342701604,2.74468984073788,24.8501820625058));
#427=CARTESIAN_POINT('',(-310.171853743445,3.25041966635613,24.7891034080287));
#428=CARTESIAN_POINT('',(-310.084390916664,3.49985334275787,24.7550510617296));
#429=CARTESIAN_POINT('',(-309.890723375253,3.99047626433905,24.6807149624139));
#430=CARTESIAN_POINT('',(-309.784511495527,4.23166231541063,24.6404288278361));
#431=CARTESIAN_POINT('',(-309.550676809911,4.71154370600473,24.5532610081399));
#432=CARTESIAN_POINT('',(-309.422500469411,4.94993951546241,24.5062158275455));
#433=CARTESIAN_POINT('',(-309.148039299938,5.41520072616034,24.4076254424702));
#434=CARTESIAN_POINT('',(-309.001747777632,5.64206182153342,24.3560785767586));
#435=CARTESIAN_POINT('',(-308.692041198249,6.08301428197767,24.2497090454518));
#436=CARTESIAN_POINT('',(-308.528623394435,6.29710359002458,24.1948858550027));
#437=CARTESIAN_POINT('',(-308.185662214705,6.71140238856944,24.083253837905));
#438=CARTESIAN_POINT('',(-308.0061180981,6.91161124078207,24.0264449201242));
#439=CARTESIAN_POINT('',(-307.618984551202,7.31043905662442,23.908234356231));
#440=CARTESIAN_POINT('',(-307.410315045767,7.50799727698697,23.8467860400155));
#441=CARTESIAN_POINT('',(-306.97699477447,7.88485612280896,23.7248448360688));
#442=CARTESIAN_POINT('',(-306.752350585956,8.06416418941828,23.6643515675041));
#443=CARTESIAN_POINT('',(-306.288119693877,8.4035944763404,23.5459537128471));
#444=CARTESIAN_POINT('',(-306.048523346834,8.56370411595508,23.4880508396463));
#445=CARTESIAN_POINT('',(-305.555996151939,8.86340597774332,23.3766035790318));
#446=CARTESIAN_POINT('',(-305.303071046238,9.00300693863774,23.3230573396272));
#447=CARTESIAN_POINT('',(-304.782108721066,9.26224753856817,23.2213352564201));
#448=CARTESIAN_POINT('',(-304.51392354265,9.381619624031,23.1732338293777));
#449=CARTESIAN_POINT('',(-303.967252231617,9.59710554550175,23.0848248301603));
#450=CARTESIAN_POINT('',(-303.688770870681,9.69323000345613,23.0445137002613));
#451=CARTESIAN_POINT('',(-303.12354634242,9.86123160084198,22.9731245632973));
#452=CARTESIAN_POINT('',(-302.836806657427,9.93311880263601,22.9420427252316));
#453=CARTESIAN_POINT('',(-302.25726859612,10.0518392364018,22.890276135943));
#454=CARTESIAN_POINT('',(-301.964470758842,10.0986746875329,22.8695904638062));
#455=CARTESIAN_POINT('',(-301.397283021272,10.1641633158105,22.8405550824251));
#456=CARTESIAN_POINT('',(-301.123145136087,10.1846546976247,22.8314017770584));
#457=CARTESIAN_POINT('',(-300.573963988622,10.2034310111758,22.8230170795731));
#458=CARTESIAN_POINT('',(-300.298920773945,10.2017170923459,22.823785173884));
#459=CARTESIAN_POINT('',(-299.750116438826,10.1761058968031,22.8352153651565));
#460=CARTESIAN_POINT('',(-299.476355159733,10.1522114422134,22.8458762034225));
#461=CARTESIAN_POINT('',(-298.932183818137,10.0825193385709,22.8767185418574));
#462=CARTESIAN_POINT('',(-298.661773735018,10.036721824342,22.8968999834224));
#463=CARTESIAN_POINT('',(-298.137843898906,9.92616689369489,22.9450358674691));
#464=CARTESIAN_POINT('',(-297.884098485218,9.86231170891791,22.9726178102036));
#465=CARTESIAN_POINT('',(-297.382997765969,9.71557925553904,23.03505747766));
#466=CARTESIAN_POINT('',(-297.135644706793,9.63269539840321,23.0699177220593));
#467=CARTESIAN_POINT('',(-296.648856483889,9.44861946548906,23.1459174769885));
#468=CARTESIAN_POINT('',(-296.409421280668,9.34742748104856,23.1870569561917));
#469=CARTESIAN_POINT('',(-295.939722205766,9.12749285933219,23.2745112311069));
#470=CARTESIAN_POINT('',(-295.709459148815,9.00874866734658,23.3208264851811));
#471=CARTESIAN_POINT('',(-295.246047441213,8.74704987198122,23.4202869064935));
#472=CARTESIAN_POINT('',(-295.013521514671,8.60308382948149,23.4736733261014));
#473=CARTESIAN_POINT('',(-294.561253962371,8.29733760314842,23.5834808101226));
#474=CARTESIAN_POINT('',(-294.341512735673,8.13555686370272,23.6399019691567));
#475=CARTESIAN_POINT('',(-293.91587364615,7.7950990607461,23.7543403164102));
#476=CARTESIAN_POINT('',(-293.709979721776,7.61641722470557,23.8123579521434));
#477=CARTESIAN_POINT('',(-293.313168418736,7.24317940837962,23.9285300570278));
#478=CARTESIAN_POINT('',(-293.122251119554,7.04862334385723,23.9866845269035));
#479=CARTESIAN_POINT('',(-292.743809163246,6.63071217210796,24.1056847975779));
#480=CARTESIAN_POINT('',(-292.55742501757,6.40629638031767,24.1664398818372));
#481=CARTESIAN_POINT('',(-292.204265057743,5.94187315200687,24.2848006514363));
#482=CARTESIAN_POINT('',(-292.037482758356,5.70187091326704,24.342407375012));
#483=CARTESIAN_POINT('',(-291.724582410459,5.20746466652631,24.4529448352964));
#484=CARTESIAN_POINT('',(-291.578479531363,4.95305027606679,24.5058721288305));
#485=CARTESIAN_POINT('',(-291.308321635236,4.43161956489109,24.6055111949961));
#486=CARTESIAN_POINT('',(-291.184264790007,4.16460429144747,24.652223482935));
#487=CARTESIAN_POINT('',(-290.961330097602,3.62458274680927,24.7373360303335));
#488=CARTESIAN_POINT('',(-290.862047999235,3.35176427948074,24.7758679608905));
#489=CARTESIAN_POINT('',(-290.686882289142,2.79769806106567,24.8445322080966));
#490=CARTESIAN_POINT('',(-290.610996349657,2.51645115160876,24.8746653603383));
#491=CARTESIAN_POINT('',(-290.483615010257,1.94846806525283,24.925580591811));
#492=CARTESIAN_POINT('',(-290.432054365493,1.66174874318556,24.9463876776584));
#493=CARTESIAN_POINT('',(-290.353648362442,1.08455530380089,24.9781334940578));
#494=CARTESIAN_POINT('',(-290.326784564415,0.794084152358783,24.9890795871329));
#495=CARTESIAN_POINT('',(-290.308274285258,0.41925327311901,24.9966251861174));
#496=CARTESIAN_POINT('',(-290.305172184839,0.335440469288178,24.9978901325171));
#497=CARTESIAN_POINT('',(-290.301034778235,0.167754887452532,24.9995777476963));
#498=CARTESIAN_POINT('',(-290.299999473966,0.0838821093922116,25.0000004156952));
#499=CARTESIAN_POINT('',(-290.3,0.,25.0000000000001));
#500=B_SPLINE_CURVE_WITH_KNOTS('',3,(#346,#347,#348,#349,#350,#351,#352,#353,#354,#355,#356,
#357,#358,#359,#360,#361,#362,#363,#364,#365,#366,#367,#368,#369,#370,#371,#372,#373,#374,#375,
#376,#377,#378,#379,#380,#381,#382,#383,#384,#385,#386,#387,#388,#389,#390,#391,#392,#393,#394,
#395,#396,#397,#398,#399,#400,#401,#402,#403,#404,#405,#406,#407,#408,#409,#410,#411,#412,#413,
#414,#415,#416,#417,#418,#419,#420,#421,#422,#423,#424,#425,#426,#427,#428,#429,#430,#431,#432,
#433,#434,#435,#436,#437,#438,#439,#440,#441,#442,#443,#444,#445,#446,#447,#448,#449,#450,#451,
#452,#453,#454,#455,#456,#457,#458,#459,#460,#461,#462,#463,#464,#465,#466,#467,#468,#469,#470,
#471,#472,#473,#474,#475,#476,#477,#478,#479,#480,#481,#482,#483,#484,#485,#486,#487,#488,#489,
#490,#491,#492,#493,#494,#495,#496,#497,#498,#499),.UNSPECIFIED.,.T.,.F.,(4,2,2,2,2,2,2,2,2,2,2,
2,2,2,2,2,2,2,2,2,2,2,2,2,2,2,2,2,2,2,2,2,2,2,2,2,2,2,2,2,2,2,2,2,2,2,2,2,2,2,2,2,2,2,2,2,2,2,2,
2,2,2,2,2,2,2,2,2,2,2,2,2,2,2,2,2,4),(0.,0.821282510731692,1.64310002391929,2.46678893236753,
3.29053450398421,4.11145536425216,4.93240659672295,5.75287692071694,6.5736481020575,
8.28632730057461,9.99987156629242,10.8977043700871,11.7951659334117,12.6924815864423,
13.5897335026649,14.4451011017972,15.3004432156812,16.1554032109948,17.0103209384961,
17.8026371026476,18.5952268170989,19.3876213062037,20.1803262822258,20.9891888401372,
21.7984031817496,22.6076923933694,23.4170251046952,24.2918919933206,25.1664799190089,
26.0415974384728,26.9163627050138,27.8100268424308,28.7037123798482,29.5970151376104,
30.4902531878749,31.3288614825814,32.1674356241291,33.0058116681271,33.8441704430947,
34.642927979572,35.4416540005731,36.2403024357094,37.0392567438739,37.8625419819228,
38.686132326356,39.5098549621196,40.3336154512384,41.2141546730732,42.0943334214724,
42.9750858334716,43.8554618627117,44.7467007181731,45.637531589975,46.527992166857,
47.4183738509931,48.2424819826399,49.0665474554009,49.8905080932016,50.7144636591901,
51.5029072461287,52.2916242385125,53.0803372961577,53.8691202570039,54.7041620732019,
55.5392299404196,56.3745343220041,57.2098431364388,58.1027169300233,58.9952944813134,
59.8885234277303,60.7816782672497,61.6591338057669,62.5365020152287,63.4115033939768,
64.2858509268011,64.5374707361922,64.7890907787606),.UNSPECIFIED.);
#501=CARTESIAN_POINT('',(-290.3,0.,25.0000000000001));
#502=VERTEX_POINT('',#501);
#503=EDGE_CURVE('E46',#502,#502,#500,.T.);
#504=ORIENTED_EDGE('',*,*,#503,.T.);
#505=EDGE_LOOP('',(#504));
#506=FACE_BOUND('',#505,.T.);
#507=CARTESIAN_POINT('',(317.5,0.,0.));
#508=DIRECTION('',(-1.,0.,0.));
#509=DIRECTION('',(0.,0.,1.));
#510=AXIS2_PLACEMENT_3D('',#507,#508,#509);
#511=CIRCLE('',#510,25.);
#512=CARTESIAN_POINT('',(317.5,0.,25.));
#513=VERTEX_POINT('',#512);
#514=EDGE_CURVE('E81',#513,#513,#511,.T.);
#515=ORIENTED_EDGE('',*,*,#514,.T.);
#516=EDGE_LOOP('',(#515));
#517=FACE_BOUND('',#516,.T.);
#518=CARTESIAN_POINT('',(-317.5,0.,0.));
#519=DIRECTION('',(1.,0.,0.));
#520=DIRECTION('',(0.,0.,-1.));
#521=AXIS2_PLACEMENT_3D('',#518,#519,#520);
#522=CIRCLE('',#521,25.);
#523=CARTESIAN_POINT('',(-317.5,0.,-25.));
#524=VERTEX_POINT('',#523);
#525=EDGE_CURVE('E84',#524,#524,#522,.T.);
#526=ORIENTED_EDGE('',*,*,#525,.T.);
#527=EDGE_LOOP('',(#526));
#528=FACE_BOUND('',#527,.T.);
#529=CARTESIAN_POINT('',(277.5,21.6506350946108,-12.5));
#530=CARTESIAN_POINT('',(277.174171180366,21.6506369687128,-12.4999985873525));
#531=CARTESIAN_POINT('',(276.848313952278,21.6580155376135,-12.4872432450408));
#532=CARTESIAN_POINT('',(276.199110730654,21.6872558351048,-12.4363891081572));
#533=CARTESIAN_POINT('',(275.87576597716,21.7091243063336,-12.3982785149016));
#534=CARTESIAN_POINT('',(275.233635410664,21.7665787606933,-12.297130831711));
#535=CARTESIAN_POINT('',(274.914859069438,21.802189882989,-12.2340480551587));
#536=CARTESIAN_POINT('',(274.284773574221,21.8858435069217,-12.0837589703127));
#537=CARTESIAN_POINT('',(273.973463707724,21.9338848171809,-11.9965549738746));
#538=CARTESIAN_POINT('',(273.361908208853,22.0405000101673,-11.7995262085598));
#539=CARTESIAN_POINT('',(273.061610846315,22.0990140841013,-11.6898294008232));
#540=CARTESIAN_POINT('',(272.471827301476,22.2249725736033,-11.4485414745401));
#541=CARTESIAN_POINT('',(272.182345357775,22.2924204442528,-11.3169418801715));
#542=CARTESIAN_POINT('',(271.332535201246,22.5052717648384,-10.8909843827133));
#543=CARTESIAN_POINT('',(270.7902638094,22.6612898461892,-10.5652792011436));
#544=CARTESIAN_POINT('',(269.721020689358,22.9996468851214,-9.80822889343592));
#545=CARTESIAN_POINT('',(269.198999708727,23.1830954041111,-9.37038644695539));
#546=CARTESIAN_POINT('',(268.474067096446,23.4556474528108,-8.65437620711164));
#547=CARTESIAN_POINT('',(268.241957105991,23.5461267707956,-8.40562738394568));
#548=CARTESIAN_POINT('',(267.798332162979,23.7240607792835,-7.88944454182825));
#549=CARTESIAN_POINT('',(267.586809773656,23.8115165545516,-7.62201733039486));
#550=CARTESIAN_POINT('',(267.172039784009,23.9870610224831,-7.05096348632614));
#551=CARTESIAN_POINT('',(266.970324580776,24.0747909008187,-6.74611185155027));
#552=CARTESIAN_POINT('',(266.593493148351,24.2419754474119,-6.11818329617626));
#553=CARTESIAN_POINT('',(266.418378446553,24.3214296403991,-5.79510533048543));
#554=CARTESIAN_POINT('',(266.09656348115,24.4697359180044,-5.1329394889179));
#555=CARTESIAN_POINT('',(265.949849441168,24.5385931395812,-4.79385947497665));
#556=CARTESIAN_POINT('',(265.686421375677,24.663681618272,-4.10199116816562));
#557=CARTESIAN_POINT('',(265.569704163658,24.7199142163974,-3.7492043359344));
#558=CARTESIAN_POINT('',(265.374964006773,24.8145076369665,-3.0582701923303));
#559=CARTESIAN_POINT('',(265.294779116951,24.8538552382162,-2.72086672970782));
#560=CARTESIAN_POINT('',(265.162586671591,24.9190379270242,-2.0392914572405));
#561=CARTESIAN_POINT('',(265.110577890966,24.9448736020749,-1.69511994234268));
#562=CARTESIAN_POINT('',(265.035450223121,24.9822725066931,-1.00304268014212));
#563=CARTESIAN_POINT('',(265.012316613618,24.9938430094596,-0.655138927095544));
#564=CARTESIAN_POINT('',(264.995214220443,25.0023919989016,0.0415551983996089));
#565=CARTESIAN_POINT('',(265.001243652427,24.9993713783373,0.390345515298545));
#566=CARTESIAN_POINT('',(265.040579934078,24.9797298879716,1.05545670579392));
#567=CARTESIAN_POINT('',(265.071465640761,24.9643162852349,1.37196006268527));
#568=CARTESIAN_POINT('',(265.157103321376,24.9217919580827,2.00090286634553));
#569=CARTESIAN_POINT('',(265.211853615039,24.8946820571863,2.3133425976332));
#570=CARTESIAN_POINT('',(265.344624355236,24.8294144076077,2.93205832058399));
#571=CARTESIAN_POINT('',(265.422645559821,24.7912562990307,3.2383341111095));
#572=CARTESIAN_POINT('',(265.601164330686,24.7047808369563,3.84278923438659));
#573=CARTESIAN_POINT('',(265.701662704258,24.6564631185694,4.14096827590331));
#574=CARTESIAN_POINT('',(265.925732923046,24.5500266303,4.73153890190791));
#575=CARTESIAN_POINT('',(266.049603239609,24.4917821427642,5.02379438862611));
#576=CARTESIAN_POINT('',(266.318422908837,24.3672624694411,5.59664626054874));
#577=CARTESIAN_POINT('',(266.463372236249,24.3009872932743,5.87724265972));
#578=CARTESIAN_POINT('',(266.773277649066,24.1618170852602,6.42546402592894));
#579=CARTESIAN_POINT('',(266.938235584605,24.0889214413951,6.69308779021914));
#580=CARTESIAN_POINT('',(267.287133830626,23.9380009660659,7.21427443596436));
#581=CARTESIAN_POINT('',(267.471081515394,23.859974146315,7.46783179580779));
#582=CARTESIAN_POINT('',(267.875090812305,23.6928666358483,7.9829910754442));
#583=CARTESIAN_POINT('',(268.096922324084,23.6034377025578,8.24309375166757));
#584=CARTESIAN_POINT('',(268.560729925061,23.4225308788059,8.74390948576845));
#585=CARTESIAN_POINT('',(268.802707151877,23.331052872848,8.9846214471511));
#586=CARTESIAN_POINT('',(269.305731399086,23.1482419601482,9.44565668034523));
#587=CARTESIAN_POINT('',(269.566790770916,23.0569091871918,9.66596653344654));
#588=CARTESIAN_POINT('',(270.106662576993,22.8767716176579,10.084906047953));
#589=CARTESIAN_POINT('',(270.385478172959,22.7879672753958,10.2835318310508));
#590=CARTESIAN_POINT('',(270.977913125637,22.6097947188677,10.6698301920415));
#591=CARTESIAN_POINT('',(271.29261801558,22.520752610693,10.8559934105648));
#592=CARTESIAN_POINT('',(271.938816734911,22.3512779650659,11.2007713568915));
#593=CARTESIAN_POINT('',(272.270302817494,22.2708415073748,11.3593986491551));
#594=CARTESIAN_POINT('',(272.948003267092,22.1215174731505,11.6475234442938));
#595=CARTESIAN_POINT('',(273.294208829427,22.0526231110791,11.7770380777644));
#596=CARTESIAN_POINT('',(273.999054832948,21.9291206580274,12.0054389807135));
#597=CARTESIAN_POINT('',(274.357693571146,21.874510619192,12.104329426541));
#598=CARTESIAN_POINT('',(275.055630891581,21.7856557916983,12.26347567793));
#599=CARTESIAN_POINT('',(275.394211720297,21.7501406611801,12.3261709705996));
#600=CARTESIAN_POINT('',(276.076657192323,21.6947067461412,12.4234802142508));
#601=CARTESIAN_POINT('',(276.420521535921,21.6747870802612,12.4580957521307));
#602=CARTESIAN_POINT('',(277.110288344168,21.6514003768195,12.4986965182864));
#603=CARTESIAN_POINT('',(277.456189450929,21.6479233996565,12.5046990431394));
#604=CARTESIAN_POINT('',(278.147053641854,21.6575485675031,12.4880218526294));
#605=CARTESIAN_POINT('',(278.492016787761,21.6706495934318,12.4653440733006));
#606=CARTESIAN_POINT('',(279.140212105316,21.71053573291,12.3957257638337));
#607=CARTESIAN_POINT('',(279.443868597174,21.7356609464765,12.3517217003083));
#608=CARTESIAN_POINT('',(280.046053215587,21.7977675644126,12.241785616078));
#609=CARTESIAN_POINT('',(280.344579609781,21.8347528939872,12.1758463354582));
#610=CARTESIAN_POINT('',(280.934530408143,21.919415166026,12.0227647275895));
#611=CARTESIAN_POINT('',(281.225955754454,21.9670906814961,11.9356252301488));
#612=CARTESIAN_POINT('',(281.800293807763,22.0717635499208,11.7409310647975));
#613=CARTESIAN_POINT('',(282.083203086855,22.1287645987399,11.6333683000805));
#614=CARTESIAN_POINT('',(282.651815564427,22.2533312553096,11.3933466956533));
#615=CARTESIAN_POINT('',(282.937052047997,22.3212614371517,11.2599724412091));
#616=CARTESIAN_POINT('',(283.495464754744,22.4638079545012,10.9728312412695));
#617=CARTESIAN_POINT('',(283.768635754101,22.5384271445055,10.8190555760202));
#618=CARTESIAN_POINT('',(284.301747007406,22.692479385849,10.4920939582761));
#619=CARTESIAN_POINT('',(284.561684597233,22.7719133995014,10.3189041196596));
#620=CARTESIAN_POINT('',(285.067293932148,22.933742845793,9.95405785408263));
#621=CARTESIAN_POINT('',(285.312964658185,23.0161384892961,9.76240011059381));
#622=CARTESIAN_POINT('',(285.819200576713,23.192583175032,9.33615452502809));
#623=CARTESIAN_POINT('',(286.077725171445,23.2867891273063,9.09920221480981));
#624=CARTESIAN_POINT('',(286.574069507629,23.4741545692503,8.60430434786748));
#625=CARTESIAN_POINT('',(286.8118953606,23.5673143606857,8.34636503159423));
#626=CARTESIAN_POINT('',(287.265738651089,23.7502946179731,7.81048740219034));
#627=CARTESIAN_POINT('',(287.481739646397,23.8401125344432,7.53253427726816));
#628=CARTESIAN_POINT('',(287.890188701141,24.0139935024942,6.95830888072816));
#629=CARTESIAN_POINT('',(288.082646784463,24.0980589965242,6.66204448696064));
#630=CARTESIAN_POINT('',(288.447419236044,24.2604327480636,6.04450287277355));
#631=CARTESIAN_POINT('',(288.619057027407,24.3385268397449,5.72276854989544));
#632=CARTESIAN_POINT('',(288.934338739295,24.4841693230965,5.06353477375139));
#633=CARTESIAN_POINT('',(289.077981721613,24.5517173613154,4.72603479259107));
#634=CARTESIAN_POINT('',(289.335540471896,24.6742211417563,4.03792427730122));
#635=CARTESIAN_POINT('',(289.44947747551,24.7291858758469,3.6873233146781));
#636=CARTESIAN_POINT('',(289.646273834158,24.8248778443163,2.97561663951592));
#637=CARTESIAN_POINT('',(289.729136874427,24.8656067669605,2.61451217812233));
#638=CARTESIAN_POINT('',(289.856486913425,24.9284979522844,1.9185062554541));
#639=CARTESIAN_POINT('',(289.903798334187,24.9520213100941,1.584242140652));
#640=CARTESIAN_POINT('',(289.971233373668,24.985611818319,0.912314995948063));
#641=CARTESIAN_POINT('',(289.99135871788,24.9956798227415,0.5746521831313));
#642=CARTESIAN_POINT('',(290.004158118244,25.0020787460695,-0.101219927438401));
#643=CARTESIAN_POINT('',(289.996840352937,24.9984137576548,-0.439429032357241));
#644=CARTESIAN_POINT('',(289.954867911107,24.9774578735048,-1.11371445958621));
#645=CARTESIAN_POINT('',(289.920213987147,24.96016735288,-1.44979084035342));
#646=CARTESIAN_POINT('',(289.827199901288,24.9140191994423,-2.09506424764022));
#647=CARTESIAN_POINT('',(289.770555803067,24.8860005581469,-2.4045710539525));
#648=CARTESIAN_POINT('',(289.634428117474,24.8191625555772,-3.01730683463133));
#649=CARTESIAN_POINT('',(289.554945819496,24.7803438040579,-3.32053616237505));
#650=CARTESIAN_POINT('',(289.373924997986,24.6927888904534,-3.91887965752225));
#651=CARTESIAN_POINT('',(289.272384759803,24.644051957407,-4.21399319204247));
#652=CARTESIAN_POINT('',(289.048169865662,24.5377360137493,-4.79443241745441));
#653=CARTESIAN_POINT('',(288.925494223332,24.4801565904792,-5.07975765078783));
#654=CARTESIAN_POINT('',(288.654353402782,24.3547642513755,-5.65106966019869));
#655=CARTESIAN_POINT('',(288.505013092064,24.2866201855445,-5.9365681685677));
#656=CARTESIAN_POINT('',(288.185545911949,24.1435393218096,-6.49402514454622));
#657=CARTESIAN_POINT('',(288.015411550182,24.0686000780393,-6.76597868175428));
#658=CARTESIAN_POINT('',(287.655496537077,23.9135470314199,-7.29508667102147));
#659=CARTESIAN_POINT('',(287.465711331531,23.8334320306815,-7.55223767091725));
#660=CARTESIAN_POINT('',(287.06763874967,23.6697443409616,-8.05059010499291));
#661=CARTESIAN_POINT('',(286.859351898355,23.5861717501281,-8.29179199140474));
#662=CARTESIAN_POINT('',(286.403667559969,23.4089075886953,-8.78049915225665));
#663=CARTESIAN_POINT('',(286.154441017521,23.3150375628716,-9.02623729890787));
#664=CARTESIAN_POINT('',(285.636194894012,23.127673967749,-9.49603431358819));
#665=CARTESIAN_POINT('',(285.367174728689,23.0341804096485,-9.72009254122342));
#666=CARTESIAN_POINT('',(284.810415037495,22.8500132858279,-10.1454748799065));
#667=CARTESIAN_POINT('',(284.522659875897,22.7593421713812,-10.3467796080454));
#668=CARTESIAN_POINT('',(283.92997134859,22.5834994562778,-10.7251617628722));
#669=CARTESIAN_POINT('',(283.625035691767,22.498328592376,-10.9022359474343));
#670=CARTESIAN_POINT('',(282.989532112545,22.333558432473,-11.2360101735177));
#671=CARTESIAN_POINT('',(282.658456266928,22.2542245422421,-11.3918772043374));
#672=CARTESIAN_POINT('',(281.981840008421,22.1071923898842,-11.6746502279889));
#673=CARTESIAN_POINT('',(281.636307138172,22.0394881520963,-11.801571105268));
#674=CARTESIAN_POINT('',(280.933986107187,21.9185525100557,-12.0246888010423));
#675=CARTESIAN_POINT('',(280.577229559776,21.8652839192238,-12.1209646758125));
#676=CARTESIAN_POINT('',(279.854768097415,21.7753691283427,-12.2817688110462));
#677=CARTESIAN_POINT('',(279.489069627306,21.7387113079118,-12.3463192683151));
#678=CARTESIAN_POINT('',(278.852505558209,21.6911886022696,-12.4295575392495));
#679=CARTESIAN_POINT('',(278.582939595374,21.6760179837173,-12.4559482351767));
#680=CARTESIAN_POINT('',(278.042255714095,21.6557401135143,-12.4911706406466));
#681=CARTESIAN_POINT('',(277.771137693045,21.6506335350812,-12.5000011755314));
#682=CARTESIAN_POINT('',(277.5,21.6506350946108,-12.5));
#683=B_SPLINE_CURVE_WITH_KNOTS('',3,(#529,#530,#531,#532,#533,#534,#535,#536,#537,#538,#539,
#540,#541,#542,#543,#544,#545,#546,#547,#548,#549,#550,#551,#552,#553,#554,#555,#556,#557,#558,
#559,#560,#561,#562,#563,#564,#565,#566,#567,#568,#569,#570,#571,#572,#573,#574,#575,#576,#577,
#578,#579,#580,#581,#582,#583,#584,#585,#586,#587,#588,#589,#590,#591,#592,#593,#594,#595,#596,
#597,#598,#599,#600,#601,#602,#603,#604,#605,#606,#607,#608,#609,#610,#611,#612,#613,#614,#615,
#616,#617,#618,#619,#620,#621,#622,#623,#624,#625,#626,#627,#628,#629,#630,#631,#632,#633,#634,
#635,#636,#637,#638,#639,#640,#641,#642,#643,#644,#645,#646,#647,#648,#649,#650,#651,#652,#653,
#654,#655,#656,#657,#658,#659,#660,#661,#662,#663,#664,#665,#666,#667,#668,#669,#670,#671,#672,
#673,#674,#675,#676,#677,#678,#679,#680,#681,#682),.UNSPECIFIED.,.T.,.F.,(4,2,2,2,2,2,2,2,2,2,2,
2,2,2,2,2,2,2,2,2,2,2,2,2,2,2,2,2,2,2,2,2,2,2,2,2,2,2,2,2,2,2,2,2,2,2,2,2,2,2,2,2,2,2,2,2,2,2,2,
2,2,2,2,2,2,2,2,2,2,2,2,2,2,2,2,2,4),(0.,0.977205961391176,1.95486696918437,2.93432493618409,
3.91368906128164,4.88762893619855,5.86194658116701,7.80874820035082,9.91611803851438,
10.9713526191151,12.0262045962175,13.1525478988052,14.2789558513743,15.4048160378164,
16.5305565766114,17.5762155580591,18.6218290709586,19.6669092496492,20.7119254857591,
21.6659378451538,22.6198830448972,23.5738593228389,24.5278698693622,25.4950080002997,
26.4621449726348,27.4293714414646,28.39697493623,29.4558985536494,30.5148820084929,
31.5745570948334,32.6344214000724,33.7619649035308,34.8889925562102,36.0153552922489,
37.1415643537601,38.1785811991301,39.2155394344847,40.251870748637,41.2881321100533,
42.2106469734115,43.1334674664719,44.0561648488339,44.9792288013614,45.9446183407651,
46.9104218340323,47.8764189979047,48.8424850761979,49.9306247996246,51.0184421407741,
52.1070729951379,53.1952387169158,54.3125134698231,55.429825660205,56.5463369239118,
57.6627157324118,58.6766202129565,59.6904603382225,60.7039983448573,61.7175084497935,
62.6641089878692,63.6106560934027,64.5572768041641,65.5039417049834,66.4908805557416,
67.478176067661,68.4657009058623,69.4531977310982,70.5391008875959,71.6250361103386,
72.71188954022,73.7988882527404,74.9206611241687,76.0418558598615,77.1601343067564,
78.2776292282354,79.0907545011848,79.9039341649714),.UNSPECIFIED.);
#684=CARTESIAN_POINT('',(277.5,21.6506350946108,-12.5));
#685=VERTEX_POINT('',#684);
#686=EDGE_CURVE('E10',#685,#685,#683,.T.);
#687=ORIENTED_EDGE('',*,*,#686,.F.);
#688=EDGE_LOOP('',(#687));
#689=FACE_BOUND('',#688,.T.);
#690=ADVANCED_FACE('F28',(#184,#345,#506,#517,#528,#689),#23,.T.);
#691=CARTESIAN_POINT('',(-319.5,0.,0.));
#692=DIRECTION('',(1.,0.,0.));
#693=DIRECTION('',(0.,0.,-1.));
#694=AXIS2_PLACEMENT_3D('',#691,#692,#693);
#695=PLANE('',#694);
#696=CARTESIAN_POINT('',(-319.5,0.,0.));
#697=DIRECTION('',(1.,0.,0.));
#698=DIRECTION('',(0.,0.,-1.));
#699=AXIS2_PLACEMENT_3D('',#696,#697,#698);
#700=CIRCLE('',#699,23.0000000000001);
#701=CARTESIAN_POINT('',(-319.5,0.,-23.0000000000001));
#702=VERTEX_POINT('',#701);
#703=EDGE_CURVE('E75',#702,#702,#700,.F.);
#704=ORIENTED_EDGE('',*,*,#703,.T.);
#705=EDGE_LOOP('',(#704));
#706=FACE_BOUND('',#705,.T.);
#707=ADVANCED_FACE('F30',(#706),#695,.F.);
#708=CARTESIAN_POINT('',(319.5,25.,0.));
#709=DIRECTION('',(-1.,0.,0.));
#710=DIRECTION('',(0.,0.,1.));
#711=AXIS2_PLACEMENT_3D('',#708,#709,#710);
#712=PLANE('',#711);
#713=CARTESIAN_POINT('',(319.5,0.,0.));
#714=DIRECTION('',(-1.,0.,0.));
#715=DIRECTION('',(0.,0.,1.));
#716=AXIS2_PLACEMENT_3D('',#713,#714,#715);
#717=CIRCLE('',#716,23.0000000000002);
#718=CARTESIAN_POINT('',(319.5,0.,23.0000000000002));
#719=VERTEX_POINT('',#718);
#720=EDGE_CURVE('E78',#719,#719,#717,.F.);
#721=ORIENTED_EDGE('',*,*,#720,.T.);
#722=EDGE_LOOP('',(#721));
#723=FACE_BOUND('',#722,.T.);
#724=ADVANCED_FACE('F110',(#723),#712,.F.);
#725=CARTESIAN_POINT('',(317.5,0.,0.));
#726=DIRECTION('',(-1.,0.,0.));
#727=DIRECTION('',(0.,0.,1.));
#728=AXIS2_PLACEMENT_3D('',#725,#726,#727);
#729=CONICAL_SURFACE('',#728,25.,0.785398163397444);
#730=ORIENTED_EDGE('',*,*,#720,.F.);
#731=EDGE_LOOP('',(#730));
#732=FACE_BOUND('',#731,.T.);
#733=ORIENTED_EDGE('',*,*,#514,.F.);
#734=EDGE_LOOP('',(#733));
#735=FACE_BOUND('',#734,.T.);
#736=ADVANCED_FACE('F124',(#732,#735),#729,.T.);
#737=CARTESIAN_POINT('',(-319.5,0.,0.));
#738=DIRECTION('',(1.,0.,0.));
#739=DIRECTION('',(0.,0.,-1.));
#740=AXIS2_PLACEMENT_3D('',#737,#738,#739);
#741=CONICAL_SURFACE('',#740,23.0000000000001,0.785398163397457);
#742=ORIENTED_EDGE('',*,*,#525,.F.);
#743=EDGE_LOOP('',(#742));
#744=FACE_BOUND('',#743,.T.);
#745=ORIENTED_EDGE('',*,*,#703,.F.);
#746=EDGE_LOOP('',(#745));
#747=FACE_BOUND('',#746,.T.);
#748=ADVANCED_FACE('F67',(#744,#747),#741,.T.);
#749=CARTESIAN_POINT('',(-300.5,0.,-24.9999999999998));
#750=DIRECTION('',(0.,0.,1.));
#751=DIRECTION('',(1.,0.,0.));
#752=AXIS2_PLACEMENT_3D('',#749,#750,#751);
#753=CYLINDRICAL_SURFACE('',#752,10.2);
#754=ORIENTED_EDGE('',*,*,#503,.F.);
#755=EDGE_LOOP('',(#754));
#756=FACE_BOUND('',#755,.T.);
#757=ORIENTED_EDGE('',*,*,#342,.F.);
#758=EDGE_LOOP('',(#757));
#759=FACE_BOUND('',#758,.T.);
#760=ADVANCED_FACE('F62',(#756,#759),#753,.F.);
#761=CARTESIAN_POINT('',(-255.5,39.9999999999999,0.));
#762=DIRECTION('',(0.,-1.,0.));
#763=DIRECTION('',(0.,0.,-1.));
#764=AXIS2_PLACEMENT_3D('',#761,#762,#763);
#765=CYLINDRICAL_SURFACE('',#764,12.5);
#766=CARTESIAN_POINT('',(-255.5,39.9999999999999,0.));
#767=DIRECTION('',(0.,1.,0.));
#768=DIRECTION('',(0.,0.,1.));
#769=AXIS2_PLACEMENT_3D('',#766,#767,#768);
#770=CIRCLE('',#769,12.5);
#771=CARTESIAN_POINT('',(-255.5,39.9999999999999,12.5));
#772=VERTEX_POINT('',#771);
#773=EDGE_CURVE('E87',#772,#772,#770,.T.);
#774=ORIENTED_EDGE('',*,*,#773,.F.);
#775=EDGE_LOOP('',(#774));
#776=FACE_BOUND('',#775,.T.);
#777=ORIENTED_EDGE('',*,*,#181,.T.);
#778=EDGE_LOOP('',(#777));
#779=FACE_BOUND('',#778,.T.);
#780=ADVANCED_FACE('F57',(#776,#779),#765,.T.);
#781=CARTESIAN_POINT('',(-255.5,39.9999999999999,0.));
#782=DIRECTION('',(0.,1.,0.));
#783=DIRECTION('',(0.,0.,1.));
#784=AXIS2_PLACEMENT_3D('',#781,#782,#783);
#785=PLANE('',#784);
#786=ORIENTED_EDGE('',*,*,#773,.T.);
#787=EDGE_LOOP('',(#786));
#788=FACE_BOUND('',#787,.T.);
#789=ADVANCED_FACE('F61',(#788),#785,.T.);
#790=CARTESIAN_POINT('',(277.5,39.9999999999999,0.));
#791=DIRECTION('',(0.,-1.,0.));
#792=DIRECTION('',(0.,0.,-1.));
#793=AXIS2_PLACEMENT_3D('',#790,#791,#792);
#794=CYLINDRICAL_SURFACE('',#793,12.5);
#795=CARTESIAN_POINT('',(277.5,39.9999999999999,0.));
#796=DIRECTION('',(0.,1.,0.));
#797=DIRECTION('',(0.,0.,1.));
#798=AXIS2_PLACEMENT_3D('',#795,#796,#797);
#799=CIRCLE('',#798,12.5);
#800=CARTESIAN_POINT('',(277.5,39.9999999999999,12.5));
#801=VERTEX_POINT('',#800);
#802=EDGE_CURVE('E90',#801,#801,#799,.T.);
#803=ORIENTED_EDGE('',*,*,#802,.F.);
#804=EDGE_LOOP('',(#803));
#805=FACE_BOUND('',#804,.T.);
#806=ORIENTED_EDGE('',*,*,#686,.T.);
#807=EDGE_LOOP('',(#806));
#808=FACE_BOUND('',#807,.T.);
#809=ADVANCED_FACE('F96',(#805,#808),#794,.T.);
#810=CARTESIAN_POINT('',(277.5,39.9999999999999,0.));
#811=DIRECTION('',(0.,1.,0.));
#812=DIRECTION('',(0.,0.,1.));
#813=AXIS2_PLACEMENT_3D('',#810,#811,#812);
#814=PLANE('',#813);
#815=ORIENTED_EDGE('',*,*,#802,.T.);
#816=EDGE_LOOP('',(#815));
#817=FACE_BOUND('',#816,.T.);
#818=ADVANCED_FACE('F94',(#817),#814,.T.);
#819=CLOSED_SHELL('',(#690,#707,#724,#736,#748,#760,#780,#789,#809,#818));
#820=MANIFOLD_SOLID_BREP('B2',#819);
#821=ADVANCED_BREP_SHAPE_REPRESENTATION('',(#18,#820),#14);
#822=SHAPE_DEFINITION_REPRESENTATION(#9,#821);
ENDSEC;
END-ISO-10303-21;
